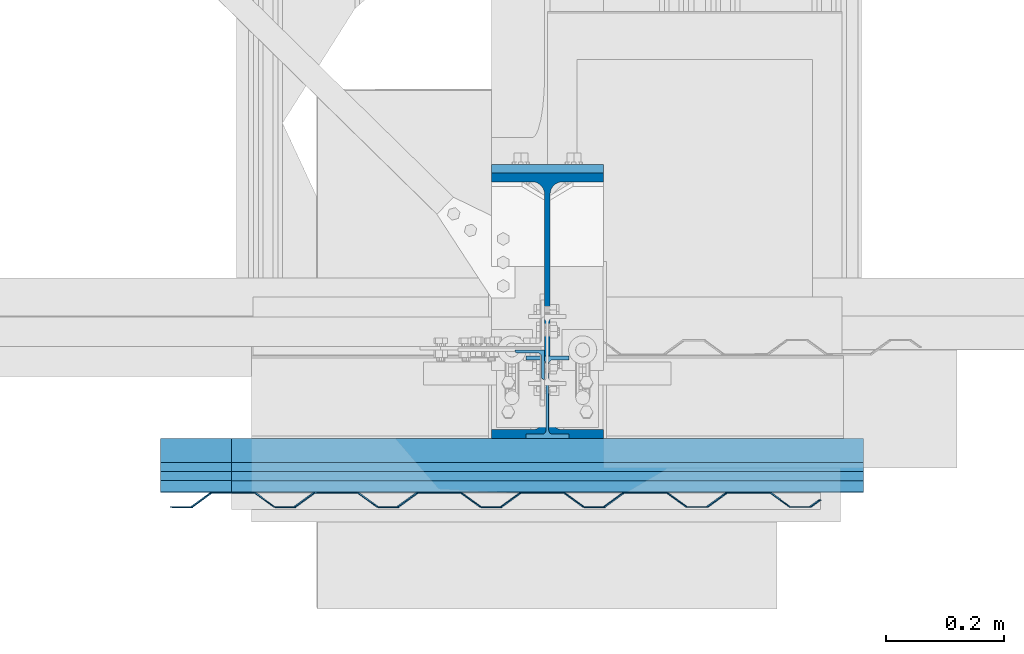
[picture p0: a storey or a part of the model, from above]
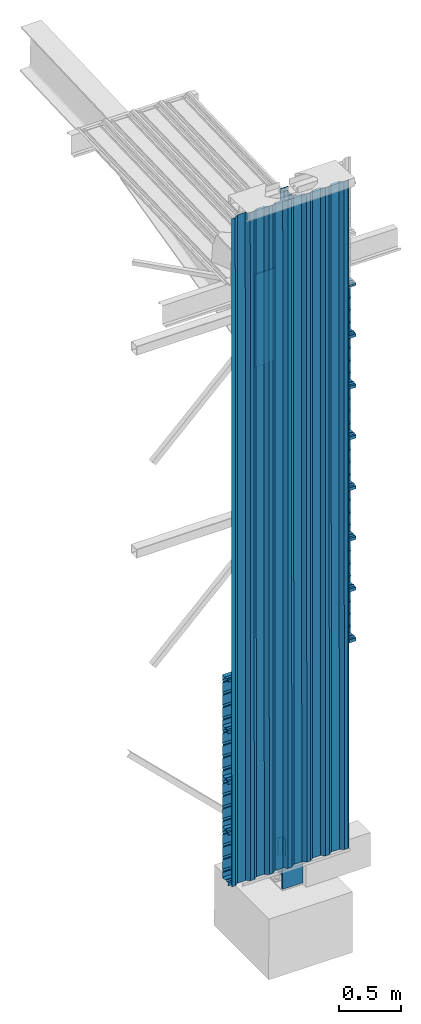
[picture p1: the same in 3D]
Properties of the parts of a building model (IFC2X3)

# File
Description: ViewDefinition [CoordinationView, QuantityTakeOffAddOnView]
File name: u52_2007v4.ifc
Time: 2011-07-12T17:19:12
Author: PORTCM01/professeur
Organization: Structural Designer
Written by: IFC Database Version:Work
Made in: Tekla Structures 18.1 Build:12518/10.9.2012, IFC Export Version: 309Mar 29 2012

# IfcSite, Undefined
RefElevation: 0 mm

# IfcBuildingStorey, Undefined
In: Undefined
Elevation: 0 mm

# IfcBeam: 100*8 (3)
In: Undefined
Description: 100*8; Material: STEEL/S235JR
Tekla Common - Phase: 1; Class: 2; Grade: S235JR; Profile: 100*8; sets with these values: 2
Tekla Quantity - Height: 100 mm; Width: 8 mm; sets with these values: 2
Name | Center of gravity Z (mm) | Center of gravity Y (mm) | Center of gravity X (mm) | Bottom elevation | Top elevation | Part mark | Assembly mark | Name | Net weight (kg) = Gross weight (kg) = Weight (kg) = NetWeight (kg) | Net volume (m3) = Gross volume (m3) = NetVolume (m3) | Gross footprint area (m2) | Area per tons (m2) | Net surface area (m2) = Gross area (m2) = OuterSurfaceArea (m2) | Tekla Quantity, Length (mm) = BaseQuantities, Length (mm)
plat | 5896.02 | -156.908 | 44.4493 | +5.892 | +5.900 | A13 | A13 | plat | 0.52752 | 0.0000672 | 0.0084 | 37.428 | 0.019744 | 84
ABOUT BAIONNETTE | 6526 | -155 | 9.55507e-08 | +6.522 | +6.530 | 25(?) | P3(?) | ABOUT BAIONNETTE | 1.08456 | 0.00013816 | 0.01727 | 35.8702 | 0.0389032 | 172.7
plat | 5896.02 | -156.908 | -44.4507 | +5.892 | +5.900 | 26 | P3(?) | plat | 0.52752 | 0.0000672 | 0.0084 | 37.428 | 0.019744 | 84

# IfcBeam: 1000*0.63 (2)
In: Undefined
Description: 1000*0.63; Material: STEEL/S235JR
Tekla Common - Phase: 1; Grade: S235JR; Profile: 1000*0.63; sets with these values: 2
Tekla Quantity - Height: 1000 mm; Width: 0.63 mm; sets with these values: 2
Name | Center of gravity Z (mm) | Center of gravity Y (mm) | Center of gravity X (mm) | Bottom elevation | Top elevation | Part mark = Assembly mark | Class | Name | Net weight (kg) = Weight (kg) = NetWeight (kg) | Gross weight (kg) | Net volume (m3) = NetVolume (m3) | Gross volume (m3) | Gross footprint area (m2) | Area per tons (m2) | Net surface area (m2) = OuterSurfaceArea (m2) | Gross area (m2) | Tekla Quantity, Length (mm) = BaseQuantities, Length (mm)
BAVETTE | -2.53135 | -331.446 | -36.5 | -0.027 | +0.031 | B0(?) | 6 | BAVETTE | 0.496489 | 0.496489 | 0.000063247 | 0.000063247 | 0.00063 | 407.201 | 0.20217 | 0.20217 | 98.3257
COIFFE ACROTERE | 6582.44 | -240.452 | -1.03851 | +6.511 | +6.611 | A16(?) | 7 | COIFFE ACROTERE | 1.88091 | 2.51264 | 0.000239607 | 0.000320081 | 0 | 405.745 | 0.763172 | 1.01803 | 505.386

# IfcBeam: 1000*1.5, COSTIERE
In: Undefined
Description: 1000*1.5; Material: STEEL/S235JR
Tekla Common - Center of gravity Z: 5809.49 mm; Center of gravity Y: -69.3239 mm; Center of gravity X: 0.00000972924 mm; Bottom elevation: +5.728; Top elevation: +5.960; Part mark: A12(?); Assembly mark: A12(?); Phase: 1; Class: 2; Grade: S235JR; Profile: 1000*1.5; Name: COSTIERE; sets with these values: 2
Tekla Quantity - Net weight: 3.88528 kg; Gross weight: 3.88528 kg; Weight: 3.88528 kg; Net volume: 0.00049494 m3; Gross volume: 0.00049494 m3; Gross footprint area: 0.0015 m2; Area per tons: 170.878 m2; Net surface area: 0.66391 m2; Gross area: 0.66391 m2; Height: 1000 mm; Width: 1.5 mm; Length: 328.46 mm; sets with these values: 2
BaseQuantities - Length: 328.46 mm; OuterSurfaceArea: 0.66391 m2; NetVolume: 0.00049494 m3; NetWeight: 3.88528 kg

# IfcBeam: 200*330, LONGRINE
In: Undefined
Description: 200*330; Material: CONCRETE/C30/37
Tekla Common - Center of gravity Z: -135.07 mm; Center of gravity Y: -174.995 mm; Center of gravity X: 395 mm; Bottom elevation: -0.300; Top elevation: +0.030; Part mark: Da0(?); Assembly mark: Da0(?); Phase: 1; Class: 11; Grade: C30/37; Profile: 200*330; Name: LONGRINE; sets with these values: 2
Tekla Quantity - Net weight: 95.04 kg; Gross weight: 95.04 kg; Weight: 95.04 kg; Net volume: 0.0396 m3; Gross volume: 0.0396 m3; Gross footprint area: 0.12 m2; Area per tons: 8.08081 m2; Net surface area: 0.768 m2; Gross area: 0.768 m2; Height: 200 mm; Width: 330 mm; Length: 600 mm; sets with these values: 2
BaseQuantities - Length: 600 mm; OuterSurfaceArea: 0.768 m2; NetVolume: 0.0396 m3; NetWeight: 95.04 kg

# IfcBeam: 400*1, ELASTOPHENE SOPREMA
In: Undefined
Description: 400*1; Material: MISCELLANEOUS/NEOPRENE
Tekla Common - Center of gravity Z: 5833.66 mm; Center of gravity Y: 112.649 mm; Center of gravity X: 250 mm; Bottom elevation: +5.810; Top elevation: +5.959; Part mark: B0(?); Assembly mark: B0(?); Phase: 1; Class: 8; Grade: NEOPRENE; Profile: 400*1; Name: ELASTOPHENE SOPREMA; sets with these values: 2
Tekla Quantity - Net weight: 0.461503 kg; Gross weight: 0.461503 kg; Weight: 0.461503 kg; Net volume: 0.000256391 m3; Gross volume: 0.000256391 m3; Gross footprint area: 0.0004 m2; Area per tons: 1115.62 m2; Net surface area: 0.514863 m2; Gross area: 0.514863 m2; Height: 400 mm; Width: 1 mm; Length: 640.174 mm; sets with these values: 2
BaseQuantities - Length: 640.174 mm; OuterSurfaceArea: 0.514863 m2; NetVolume: 0.000256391 m3; NetWeight: 0.461503 kg

# IfcBeam: 80*500, PANNEAUTOIT FIBAC 2
In: Undefined
Description: 80*500; Material: MISCELLANEOUS/ISOLANT
Tekla Common - Center of gravity Z: 5776.99 mm; Center of gravity Y: 226.647 mm; Center of gravity X: 229.049 mm; Bottom elevation: +5.730; Top elevation: +5.823; Part mark: B0(?); Assembly mark: B0(?); Phase: 1; Class: 13; Grade: ISOLANT; Profile: 80*500; Name: PANNEAUTOIT FIBAC 2; sets with these values: 2
Tekla Quantity - Net weight: 0 kg; Gross weight: 0 kg; Weight: 0 kg; Net volume: 0.0201058 m3; Gross volume: 0.023111 m3; Gross footprint area: 0 m2; Net surface area: 0.808896 m2; Gross area: 0.750218 m2; Height: 80 mm; Width: 500 mm; Length: 577.774 mm; sets with these values: 2
BaseQuantities - Length: 577.774 mm; OuterSurfaceArea: 0.808896 m2; NetVolume: 0.0201058 m3; NetWeight: 0 kg

# IfcBeam: ARCLAD_FPB_MURESCO_1.500.90_BS_75 (13)
In: Undefined
Description: ARCLAD_FPB_MURESCO_1.500.90_BS_75; Material: STEEL/S235JR
Tekla Common - Part mark: A17(?); Assembly mark: A17(?); Phase: 1; Class: 3; Grade: S235JR; Profile: ARCLAD_FPB_MURESCO_1.500.90_BS_75; Name: BAC; sets with these values: 2
Tekla Quantity - Net weight: 6.45229 kg; Gross weight: 4.55687 kg; Weight: 4.55687 kg; Net volume: 0.000821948 m3; Gross volume: 0.000580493 m3; Gross footprint area: 0.064498 m2; Area per tons: 361.588 m2; Net surface area: 1.64771 m2; Gross area: 0 m2; Height: 92 mm; Width: 529 mm; Length: 1073 mm; sets with these values: 2
BaseQuantities - Length: 1073 mm; OuterSurfaceArea: 1.64771 m2; NetVolume: 0.000821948 m3; NetWeight: 6.45229 kg
Name | Center of gravity Z (mm) | Center of gravity Y (mm) | Center of gravity X (mm) | Bottom elevation | Top elevation
BAC | 273.805 | -244.806 | -120 | +0.001 | +0.530
BAC | 773.805 | -244.806 | -120 | +0.501 | +1.030
BAC | 1273.81 | -244.806 | -120 | +1.001 | +1.530
BAC | 1773.81 | -244.806 | -120 | +1.501 | +2.030
BAC | 2273.95 | -244.81 | 1.8531e-11 | +2.001 | +2.530
BAC | 3273.95 | -244.81 | 3.52429e-12 | +3.001 | +3.530
BAC | 2773.95 | -244.81 | 7.95808e-13 | +2.501 | +3.030
BAC | 3773.95 | -244.81 | -1.19371e-11 | +3.501 | +4.030
BAC | 4273.95 | -244.825 | 3.94493e-11 | +4.001 | +4.530
BAC | 4773.95 | -244.841 | -9.20863e-12 | +4.501 | +5.030
BAC | 5273.95 | -244.857 | 2.34195e-11 | +5.001 | +5.530
BAC | 5773.95 | -244.873 | 2.44427e-11 | +5.501 | +6.030
BAC | 6273.95 | -244.889 | -6.13909e-12 | +6.001 | +6.530

# IfcBeam: ARCLAD_TSE_TOITESCO_4.1035.34_SRP_75, BAC SUPPORT
In: Undefined
Description: ARCLAD_TSE_TOITESCO_4.1035.34_SRP_75; Material: STEEL/S235JR
Tekla Common - Center of gravity Z: 5743.41 mm; Center of gravity Y: 1222.38 mm; Center of gravity X: 20.6648 mm; Bottom elevation: +5.693; Top elevation: +5.806; Part mark: A11(?); Assembly mark: A11(?); Phase: 1; Class: 5; Grade: S235JR; Profile: ARCLAD_TSE_TOITESCO_4.1035.34_SRP_75; Name: BAC SUPPORT; sets with these values: 2
Tekla Quantity - Net weight: 21.597 kg; Gross weight: 16.7955 kg; Weight: 16.7955 kg; Net volume: 0.00275121 m3; Gross volume: 0.00213955 m3; Gross footprint area: 0 m2; Area per tons: 328.013 m2; Net surface area: 5.50914 m2; Gross area: 0 m2; Height: 33 mm; Width: 1060.73 mm; Length: 2406.69 mm; sets with these values: 2
BaseQuantities - Length: 2406.69 mm; OuterSurfaceArea: 5.50914 m2; NetVolume: 0.00275121 m3; NetWeight: 21.597 kg

# IfcBeam: ARVAL_FBV_HACIERBA_6.175.25_B_63 (2)
In: Undefined
Description: ARVAL_FBV_HACIERBA_6.175.25_B_63; Material: STEEL/S235JR
Tekla Common - Phase: 1; Grade: S235JR; Profile: ARVAL_FBV_HACIERBA_6.175.25_B_63; sets with these values: 2
Tekla Quantity - Gross footprint area: 0 m2; Gross area: 0 m2; Height: 25 mm; sets with these values: 2
Name | Center of gravity Z (mm) | Center of gravity Y (mm) | Center of gravity X (mm) | Bottom elevation | Top elevation | Part mark = Assembly mark | Class | Name | Net weight (kg) = NetWeight (kg) | Gross weight (kg) = Weight (kg) | Net volume (m3) = NetVolume (m3) | Gross volume (m3) | Area per tons (m2) | Net surface area (m2) = OuterSurfaceArea (m2) | Width (mm) | Tekla Quantity, Length (mm) = BaseQuantities, Length (mm)
PEAU EXTERIEURE | 3295.08 | -327.825 | -86.1097 | -0.000 | +6.590 | A15(?) | 12 | PEAU EXTERIEURE | 64.4229 | 35.0222 | 0.00820673 | 0.00446143 | 451.669 | 15.8185 | 1101.65 | 6590
CONTREBARDAGE | 6239.31 | -72.7459 | 377.01 | +5.887 | +6.591 | A14(?) | 14 | CONTREBARDAGE | 3.20425 | 3.73031 | 0.000408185 | 0.000475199 | 211.574 | 0.789236 | 538.054 | 701.919

# IfcBeam: D24 (2)
In: Undefined
Description: D24; Material: STEEL/S235JR
Tekla Common - Center of gravity Z: -525.468 mm; Center of gravity Y: -90.0942 mm; Bottom elevation: -0.735; Top elevation: -0.235; Part mark: B0(?); Assembly mark: B0(?); Phase: 1; Class: 10; Grade: S235JR; Profile: D24; Name: CROSSE; sets with these values: 2
Tekla Quantity - Net weight: 2.12597 kg; Gross weight: 2.12597 kg; Weight: 2.12597 kg; Net volume: 0.000270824 m3; Gross volume: 0.000270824 m3; Gross footprint area: 0.000432 m2; Area per tons: 22.4285 m2; Net surface area: 0.0476824 m2; Gross area: 0.0476824 m2; Height: 24 mm; Width: 24 mm; Length: 592.507 mm; sets with these values: 2
BaseQuantities - Length: 592.507 mm; OuterSurfaceArea: 0.0476824 m2; NetVolume: 0.000270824 m3; NetWeight: 2.12597 kg
Name | Center of gravity X (mm)
CROSSE | -60
CROSSE | 60

# IfcBeam: D40, CLE
In: Undefined
Description: D40; Material: STEEL/S235JR
Tekla Common - Center of gravity Z: -691 mm; Center of gravity Y: -115.001 mm; Center of gravity X: -3.18869e-09 mm; Bottom elevation: -0.711; Top elevation: -0.671; Part mark: B0(?); Assembly mark: B0(?); Phase: 1; Class: 6; Grade: S235JR; Profile: D40; Name: CLE; sets with these values: 2
Tekla Quantity - Net weight: 3.9564 kg; Gross weight: 3.9564 kg; Weight: 3.9564 kg; Net volume: 0.000504 m3; Gross volume: 0.000504 m3; Gross footprint area: 0 m2; Area per tons: 13.7948 m2; Net surface area: 0.0545779 m2; Gross area: 0.0545779 m2; Height: 40 mm; Width: 40 mm; Length: 420 mm; sets with these values: 2
BaseQuantities - Length: 420 mm; OuterSurfaceArea: 0.0545779 m2; NetVolume: 0.000504 m3; NetWeight: 3.9564 kg

# IfcBeam: IPE120, BECHE
In: Undefined
Description: IPE120; Material: STEEL/S235JR
Tekla Common - Center of gravity Z: -350 mm; Center of gravity Y: -75.0003 mm; Center of gravity X: -3.07782e-08 mm; Bottom elevation: -0.400; Top elevation: -0.300; Part mark: E0; Assembly mark: E0(?); Phase: 1; Class: 2; Grade: S235JR; Profile: IPE120; Name: BECHE; sets with these values: 2
Tekla Quantity - Net weight: 1.00398 kg; Gross weight: 1.0362 kg; Weight: 1.0362 kg; Net volume: 0.000127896 m3; Gross volume: 0.000132 m3; Gross footprint area: 0.00127896 m2; Area per tons: 45.8406 m2; Net surface area: 0.0512779 m2; Gross area: 0.0475 m2; Height: 120 mm; Width: 64 mm; Length: 100 mm; sets with these values: 2
BaseQuantities - Length: 100 mm; OuterSurfaceArea: 0.0475 m2; NetVolume: 0.000127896 m3; NetWeight: 1.00398 kg

# IfcBeam: IPE450 (2)
In: Undefined
Description: IPE450; Material: STEEL/S235JR
Tekla Common - Assembly mark: A1(?); Phase: 1; Grade: S235JR; Profile: IPE450; sets with these values: 2
Tekla Quantity - Gross footprint area: 0 m2; Area per tons: 20.6942 m2; Width: 190 mm; sets with these values: 2
Name | Center of gravity Z (mm) | Center of gravity Y (mm) | Center of gravity X (mm) | Bottom elevation | Top elevation | Part mark | Class | Name | Net weight (kg) = NetWeight (kg) | Gross weight (kg) = Weight (kg) | Net volume (m3) = NetVolume (m3) | Gross volume (m3) | Net surface area (m2) | Gross area (m2) = OuterSurfaceArea (m2) | Height (mm) | Tekla Quantity, Length (mm) = BaseQuantities, Length (mm)
JARRET | 4902.21 | 1165.32 | 2.32655e-12 | +4.602 | +5.146 | 3(?) | 99 | JARRET | 165.891 | 180.998 | 0.0211326 | 0.0230571 | 3.66903 | 3.74561 | 444.517 | 2333.71
POUTRE | 5359.44 | 2124.5 | 1.81463e-12 | +5.059 | +5.660 | 2 | 1 | POUTRE | 281.402 | 293.247 | 0.0358473 | 0.0373563 | 6.20963 | 6.06852 | 450 | 3781.01

# IfcBeam: L40*4, DIAGONALE PAV
In: Undefined
Description: L40*4; Material: STEEL/S235JR
Tekla Common - Center of gravity Z: 5514.53 mm; Center of gravity Y: 477.806 mm; Center of gravity X: -499.603 mm; Bottom elevation: +5.472; Top elevation: +5.540; Part mark: A4(?); Assembly mark: A4(?); Phase: 1; Class: 9; Grade: S235JR; Profile: L40*4; Name: DIAGONALE PAV; sets with these values: 2
Tekla Quantity - Net weight: 2.52387 kg; Gross weight: 2.55887 kg; Weight: 2.55887 kg; Net volume: 0.000321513 m3; Gross volume: 0.00032597 m3; Gross footprint area: 0 m2; Area per tons: 64.1079 m2; Net surface area: 0.169827 m2; Gross area: 0.164043 m2; Height: 40 mm; Width: 40 mm; Length: 1058.34 mm; sets with these values: 2
BaseQuantities - Length: 1058.34 mm; OuterSurfaceArea: 0.164043 m2; NetVolume: 0.000321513 m3; NetWeight: 2.52387 kg

# IfcBeam: L50*5 (4)
In: Undefined
Description: L50*5; Material: STEEL/S235JR
Tekla Common - Phase: 1; Grade: S235JR; Profile: L50*5; sets with these values: 2
Tekla Quantity - Area per tons: 51.4862 m2; Height: 50 mm; Width: 50 mm; sets with these values: 2
Name | Center of gravity Z (mm) | Center of gravity Y (mm) | Center of gravity X (mm) | Bottom elevation | Top elevation | Part mark = Assembly mark | Class | Name | Net weight (kg) = NetWeight (kg) | Gross weight (kg) = Weight (kg) | Net volume (m3) = NetVolume (m3) | Gross volume (m3) | Gross footprint area (m2) | Net surface area (m2) | Gross area (m2) = OuterSurfaceArea (m2) | Tekla Quantity, Length (mm) = BaseQuantities, Length (mm)
DIAGONALE CV | 2780.98 | -54.6579 | -630.38 | +2.188 | +3.359 | A8(?) | 9 | DIAGONALE CV | 6.06359 | 6.12742 | 0.000772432 | 0.000780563 | 0 | 0.326185 | 0.315477 | 1626.17
DIAGONALE CV | 762.976 | -54.6579 | -750.51 | +0.073 | +1.437 | A5(?) | 9 | DIAGONALE CV | 7.09243 | 7.16709 | 0.000903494 | 0.000913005 | 0 | 0.381369 | 0.369006 | 1902.09
DIAGONALE CV | 4780.98 | -54.6579 | -630.38 | +4.188 | +5.359 | A8(?) | 9 | DIAGONALE CV | 6.06359 | 6.12742 | 0.000772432 | 0.000780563 | 0 | 0.326185 | 0.315477 | 1626.17
ATTACHE CV | 33.0846 | -54.6559 | -19.0421 | -0.054 | +0.121 | A6(?) | 2 | ATTACHE CV | 0.652531 | 0.6594 | 0.000083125 | 0.000084 | 0.000475 | 0.03595 | 0.03395 | 175

# IfcBeam: PD48*12 (4)
In: Undefined
Description: PD48*12; Material: STEEL/S235JR
Tekla Common - Center of gravity Y: -75 mm; Part mark: E0; Assembly mark: E0(?); Phase: 1; Class: 1; Grade: S235JR; Profile: PD48*12; sets with these values: 2
Tekla Quantity - Gross footprint area: 0.001296 m2; Height: 48 mm; Width: 48 mm; sets with these values: 2
Name | Center of gravity Z (mm) | Center of gravity X (mm) | Bottom elevation | Top elevation | Name | Net weight (kg) = Gross weight (kg) = Weight (kg) = NetWeight (kg) | Net volume (m3) = Gross volume (m3) = NetVolume (m3) | Area per tons (m2) | Net surface area (m2) = Gross area (m2) = OuterSurfaceArea (m2) | Tekla Quantity, Length (mm) = BaseQuantities, Length (mm)
RONDELLE | -269 | 60 | -0.275 | -0.263 | RONDELLE | 0.122083 | 0.000015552 | 28.8079 | 0.00351696 | 12
ECROU | -251 | -60 | -0.263 | -0.239 | ECROU | 0.244166 | 0.000031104 | 21.7307 | 0.00530591 | 24
RONDELLE | -269 | -60 | -0.275 | -0.263 | RONDELLE | 0.122083 | 0.000015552 | 28.8079 | 0.00351696 | 12
ECROU | -251 | 60 | -0.263 | -0.239 | ECROU | 0.244166 | 0.000031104 | 21.7307 | 0.00530591 | 24

# IfcBeam: PL10*190, CAP PLATE
In: Undefined
Description: PL10*190; Material: STEEL/S235JR
Tekla Common - Center of gravity Z: 5509 mm; Center of gravity Y: -5.88045e-11 mm; Center of gravity X: -1.07138e-09 mm; Bottom elevation: +5.504; Top elevation: +5.514; Part mark: F3; Assembly mark: P1(?); Phase: 1; Class: 99; Grade: S235JR; Profile: PL10*190; Name: CAP PLATE; sets with these values: 2
Tekla Quantity - Net weight: 6.53277 kg; Gross weight: 6.53277 kg; Weight: 6.53277 kg; Net volume: 0.0008322 m3; Gross volume: 0.0008322 m3; Gross footprint area: 0.08322 m2; Area per tons: 27.4003 m2; Net surface area: 0.179 m2; Gross area: 0.179 m2; Height: 190 mm; Width: 10 mm; Length: 438 mm; sets with these values: 2
BaseQuantities - Length: 438 mm; OuterSurfaceArea: 0.179 m2; NetVolume: 0.0008322 m3; NetWeight: 6.53277 kg

# IfcBeam: PL10*70 (2)
In: Undefined
Description: PL10*70; Material: STEEL/S235JR
Tekla Common - Center of gravity Z: -280 mm; Center of gravity Y: -75 mm; Bottom elevation: -0.285; Top elevation: -0.275; Part mark: P2(?); Assembly mark: P2(?); Phase: 1; Class: 2; Grade: S235JR; Profile: PL10*70; Name: CONTRE PLAQUE; sets with these values: 2
Tekla Quantity - Net weight: 0.38465 kg; Gross weight: 0.38465 kg; Weight: 0.38465 kg; Net volume: 0.000049 m3; Gross volume: 0.000049 m3; Gross footprint area: 0.0049 m2; Area per tons: 32.7571 m2; Net surface area: 0.0126 m2; Gross area: 0.0126 m2; Height: 70 mm; Width: 10 mm; Length: 70 mm; sets with these values: 2
BaseQuantities - Length: 70 mm; OuterSurfaceArea: 0.0126 m2; NetVolume: 0.000049 m3; NetWeight: 0.38465 kg
Name | Center of gravity X (mm)
CONTRE PLAQUE | 60
CONTRE PLAQUE | -60

# IfcBeam: PL15*200, PLATINE
In: Undefined
Description: PL15*200; Material: STEEL/S235JR
Tekla Common - Center of gravity Z: -292.5 mm; Center of gravity Y: -75 mm; Center of gravity X: -9.02299e-14 mm; Bottom elevation: -0.300; Top elevation: -0.285; Part mark: 4(?); Assembly mark: P1(?); Phase: 1; Class: 6; Grade: S235JR; Profile: PL15*200; Name: PLATINE; sets with these values: 2
Tekla Quantity - Net weight: 7.065 kg; Gross weight: 7.065 kg; Weight: 7.065 kg; Net volume: 0.0009 m3; Gross volume: 0.0009 m3; Gross footprint area: 0.06 m2; Area per tons: 19.1083 m2; Net surface area: 0.135 m2; Gross area: 0.135 m2; Height: 200 mm; Width: 15 mm; Length: 300 mm; sets with these values: 2
BaseQuantities - Length: 300 mm; OuterSurfaceArea: 0.135 m2; NetVolume: 0.0009 m3; NetWeight: 7.065 kg

# IfcBeam: PL8*90 (2)
In: Undefined
Description: PL8*90; Material: STEEL/S235JR
Tekla Common - Center of gravity Z: 4604.44 mm; Center of gravity Y: 2.84217e-14 mm; Bottom elevation: +4.600; Top elevation: +4.608; Part mark: F2; Assembly mark: P1(?); Phase: 1; Class: 99; Grade: S235JR; Profile: PL8*90; Name: TOLE; sets with these values: 2
Tekla Quantity - Net weight: 2.33459 kg; Gross weight: 2.37384 kg; Weight: 2.33459 kg; Net volume: 0.0002974 m3; Gross volume: 0.0003024 m3; Gross footprint area: 0.037175 m2; Area per tons: 35.242 m2; Net surface area: 0.0822757 m2; Gross area: 0.08376 m2; Height: 90 mm; Width: 8 mm; Length: 420 mm; sets with these values: 2
BaseQuantities - Length: 420 mm; OuterSurfaceArea: 0.0822757 m2; NetVolume: 0.0002974 m3; NetWeight: 2.33459 kg
Name | Center of gravity X (mm)
TOLE | -50.3165
TOLE | 50.3165

# IfcBeam: TUBE-C-90*90*3 (2)
In: Undefined
Description: TUBE-C-90*90*3; Material: STEEL/S235JR
Tekla Common - Phase: 1; Class: 9; Grade: S235JR; Profile: TUBE-C-90*90*3; sets with these values: 2
Tekla Quantity - Gross weight: 11.095 kg; Weight: 11.095 kg; Gross volume: 0.00141337 m3; Area per tons: 43.5442 m2; Gross area: 0.483121 m2; Height: 90 mm; Width: 90 mm; Length: 1384.3 mm; sets with these values: 2
BaseQuantities - Length: 1384.3 mm; OuterSurfaceArea: 0.483121 m2
Name | Center of gravity Z (mm) | Center of gravity Y (mm) | Center of gravity X (mm) | Bottom elevation | Top elevation | Part mark = Assembly mark | Name | Net weight (kg) = NetWeight (kg) | Net volume (m3) = NetVolume (m3) | Gross footprint area (m2) | Net surface area (m2)
TRAVERSE CV | 3414 | -74.9963 | -705.227 | +3.369 | +3.459 | A9(?) | TRAVERSE CV | 11.3027 | 0.00143983 | 0.12369 | 0.498269
BUTON | 5413.99 | -74.9956 | -705.599 | +5.369 | +5.459 | A10(?) | BUTON | 11.2953 | 0.00143889 | 0.123475 | 0.498067

# IfcBeam: UPF-140*60*4 (4)
In: Undefined
Description: UPF-140*60*4; Material: STEEL/S235JR
Tekla Common - Phase: 1; Class: 6; Grade: S235JR; Profile: UPF-140*60*4; sets with these values: 2
Tekla Quantity - Net weight: 3.60705 kg; Gross weight: 3.53333 kg; Weight: 3.53333 kg; Net volume: 0.000459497 m3; Gross volume: 0.000450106 m3; Gross footprint area: 0.0036468 m2; Area per tons: 66.6258 m2; Net surface area: 0.235411 m2; Gross area: 0 m2; Height: 140 mm; Width: 60 mm; Length: 455.85 mm; sets with these values: 2
BaseQuantities - Length: 455.85 mm; OuterSurfaceArea: 0.235411 m2; NetVolume: 0.000459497 m3; NetWeight: 3.60705 kg
Name | Center of gravity Z (mm) | Center of gravity Y (mm) | Center of gravity X (mm) | Bottom elevation | Top elevation | Part mark = Assembly mark | Name
LISSE BASSE | 5914.88 | -154.978 | 274.424 | +5.900 | +5.960 | A20(?) | LISSE BASSE
LISSE HAUTE | 6545.33 | -155 | -274.425 | +6.530 | +6.590 | A19(?) | LISSE HAUTE
LISSE BASSE | 5914.88 | -154.978 | -274.425 | +5.900 | +5.960 | A18(?) | LISSE BASSE
LISSE HAUTE | 6545.33 | -155 | 274.425 | +6.530 | +6.590 | A19(?) | LISSE HAUTE

# IfcBeam: Z.180.150.65 (2)
In: Undefined
Description: Z.180.150.65; Material: STEEL/S235JR
Tekla Common - Phase: 1; Class: 5; Grade: S235JR; Profile: Z.180.150.65; sets with these values: 2
Tekla Quantity - Gross area: 0 m2; Height: 180 mm; Width: 123 mm; sets with these values: 2
Name | Center of gravity Z (mm) | Center of gravity Y (mm) | Center of gravity X (mm) | Bottom elevation | Top elevation | Part mark = Assembly mark | Name | Net weight (kg) = NetWeight (kg) | Gross weight (kg) = Weight (kg) | Net volume (m3) = NetVolume (m3) | Gross volume (m3) | Gross footprint area (m2) | Area per tons (m2) | Net surface area (m2) = OuterSurfaceArea (m2) | Tekla Quantity, Length (mm) = BaseQuantities, Length (mm)
PANNE SABLIERE | 5605.43 | -15.428 | 4.09273e-12 | +5.514 | +5.694 | A3(?) | PANNE SABLIERE | 8.85792 | 8.50979 | 0.0011284 | 0.00108405 | 0.14235 | 177.693 | 1.51213 | 2190
PANNE | 5684.57 | 2329.91 | 1.93268e-12 | +5.593 | +5.773 | A2(?) | PANNE | 4.81321 | 4.62404 | 0.000613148 | 0.00058905 | 0.07735 | 177.795 | 0.82213 | 1190

# IfcColumn: IPE140, BAIONNETTE
In: Undefined
Description: IPE140; Material: STEEL/S235JR
Tekla Common - Center of gravity Z: 6018 mm; Center of gravity Y: -155 mm; Center of gravity X: 3.18745e-12 mm; Bottom elevation: +5.514; Top elevation: +6.522; Part mark: 8(?); Assembly mark: P3(?); Phase: 1; Class: 7; Grade: S235JR; Profile: IPE140; Name: BAIONNETTE; sets with these values: 2
Tekla Quantity - Net weight: 12.6648 kg; Gross weight: 12.977 kg; Weight: 12.977 kg; Net volume: 0.00161335 m3; Gross volume: 0.00165312 m3; Gross footprint area: 0.00160054 m2; Area per tons: 42.7994 m2; Net surface area: 0.570302 m2; Gross area: 0.555408 m2; Height: 140 mm; Width: 73 mm; Length: 1008 mm; sets with these values: 2
BaseQuantities - Length: 1008 mm; OuterSurfaceArea: 0.555408 m2; NetVolume: 0.00161335 m3; NetWeight: 12.6648 kg

# IfcColumn: IPE450, POTEAU
In: Undefined
Description: IPE450; Material: STEEL/S235JR
Tekla Common - Center of gravity Z: 2609.5 mm; Center of gravity Y: -1.9305e-13 mm; Center of gravity X: 1.62511e-15 mm; Bottom elevation: -0.285; Top elevation: +5.504; Part mark: 1; Assembly mark: P1(?); Phase: 1; Class: 1; Grade: S235JR; Profile: IPE450; Name: POTEAU; sets with these values: 2
Tekla Quantity - Net weight: 431.875 kg; Gross weight: 448.983 kg; Weight: 448.983 kg; Net volume: 0.0550159 m3; Gross volume: 0.0571953 m3; Gross footprint area: 0.00950352 m2; Area per tons: 20.6942 m2; Net surface area: 9.51991 m2; Gross area: 9.29134 m2; Height: 450 mm; Width: 190 mm; Length: 5789 mm; sets with these values: 2
BaseQuantities - Length: 5789 mm; OuterSurfaceArea: 9.29134 m2; NetVolume: 0.0550159 m3; NetWeight: 431.875 kg

# IfcColumn: L50*5, ATTACHE CV
In: Undefined
Description: L50*5; Material: STEEL/S235JR
Tekla Common - Center of gravity Z: 33.0835 mm; Center of gravity Y: -89.3401 mm; Center of gravity X: -19.0421 mm; Bottom elevation: -0.054; Top elevation: +0.121; Part mark: A7(?); Assembly mark: A7(?); Phase: 1; Class: 2; Grade: S235JR; Profile: L50*5; Name: ATTACHE CV; sets with these values: 2
Tekla Quantity - Net weight: 0.652531 kg; Gross weight: 0.6594 kg; Weight: 0.6594 kg; Net volume: 0.000083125 m3; Gross volume: 0.000084 m3; Gross footprint area: 0.000475 m2; Area per tons: 51.4862 m2; Net surface area: 0.03595 m2; Gross area: 0.03395 m2; Height: 50 mm; Width: 50 mm; Length: 175 mm; sets with these values: 2
BaseQuantities - Length: 175 mm; OuterSurfaceArea: 0.03395 m2; NetVolume: 0.000083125 m3; NetWeight: 0.652531 kg

# IfcColumn: PL15*190, PLATINE
In: Undefined
Description: PL15*190; Material: STEEL/S235JR
Tekla Common - Center of gravity Z: 5046.5 mm; Center of gravity Y: 232.5 mm; Center of gravity X: 2.31065e-12 mm; Bottom elevation: +4.589; Top elevation: +5.504; Part mark: F1(?); Assembly mark: A1(?); Phase: 1; Class: 99; Grade: S235JR; Profile: PL15*190; Name: PLATINE; sets with these values: 2
Tekla Quantity - Net weight: 20.4708 kg; Gross weight: 20.4708 kg; Weight: 20.4708 kg; Net volume: 0.00260775 m3; Gross volume: 0.00260775 m3; Gross footprint area: 0.00285 m2; Area per tons: 18.6045 m2; Net surface area: 0.38085 m2; Gross area: 0.38085 m2; Height: 190 mm; Width: 15 mm; Length: 915 mm; sets with these values: 2
BaseQuantities - Length: 915 mm; OuterSurfaceArea: 0.38085 m2; NetVolume: 0.00260775 m3; NetWeight: 20.4708 kg

# IfcElementAssembly (57)
In: Undefined
Tekla Assembly - sets with these values: 2
Name | Assembly/Cast unit weight (kg) | Assembly/Cast unit bottom elevation | Assembly/Cast unit top elevation | Assembly/Cast unit name | Assembly/Cast unit Mark
plat | 0.52752 | +5.892 | +5.900 | plat | A13
lisseBasse | 0 | +5.900 | +5.960 | lisseBasse | A20(?)
etancheite | 0.461503 | +5.810 | +5.959 | etancheite | B0(?)
isolant | 0 | +5.730 | +5.823 | isolant | B0(?)
clé | 0 | -0.711 | -0.671 | clé | B0(?)
massif | 725.495 | -0.902 | -0.296 | massif | Da0(?) | PredefinedType: REINFORCEMENT_UNIT; Tekla Assembly - Cast unit rebar weight: 0 kg
BECHE | 0 | -0.400 | -0.300 | BECHE | E0(?)
bavette | 0.496489 | -0.027 | +0.031 | bavette | B0(?)
bac | 0 | +0.001 | +0.530 | bac | A17(?)
bac | 0 | +0.501 | +1.030 | bac | A17(?)
bac | 0 | +1.001 | +1.530 | bac | A17(?)
bac | 0 | +1.501 | +2.030 | bac | A17(?)
bac | 0 | +2.001 | +2.530 | bac | A17(?)
bac | 0 | +2.501 | +3.030 | bac | A17(?)
2 x plaque | 0.38465 | -0.285 | -0.275 | plaque | P2(?)
Assembly | 0 | -0.735 | -0.235 | Assembly | B0(?)
BARRE | 0 | -0.735 | -0.235 | BARRE | B0(?)
Assembly | 0 | -0.275 | -0.263 | Assembly | E0(?)
bac | 0 | +3.001 | +3.530 | bac | A17(?)
RONDELLE | 0 | -0.275 | -0.263 | RONDELLE | E0(?)
ECROU | 0 | -0.263 | -0.239 | ECROU | E0(?)
Assembly | 0 | -0.263 | -0.239 | Assembly | E0(?)
massif | 95.04 | -0.300 | +0.030 | massif | Da0(?) | PredefinedType: REINFORCEMENT_UNIT; Tekla Assembly - Cast unit rebar weight: 0 kg
coiffe | 1.88091 | +6.511 | +6.611 | coiffe | A16(?)
contrebardage | 0 | -0.000 | +6.590 | contrebardage | A15(?)
contrebardage | 0 | +5.887 | +6.591 | contrebardage | A14(?)
2 x lisseBasse | 0 | +6.530 | +6.590 | lisseBasse | A19(?)
bac | 0 | +3.501 | +4.030 | bac | A17(?)
bac | 0 | +4.001 | +4.530 | bac | A17(?)
bac | 0 | +4.501 | +5.030 | bac | A17(?)
bac | 0 | +5.001 | +5.530 | bac | A17(?)
bac | 0 | +5.501 | +6.030 | bac | A17(?)
lisseBasse | 0 | +5.900 | +5.960 | lisseBasse | A18(?)
costière | 3.88528 | +5.728 | +5.960 | costière | A12(?)
bac | 0 | +6.001 | +6.530 | bac | A17(?)
bac | 0 | +5.693 | +5.806 | bac | A11(?)
GOUSSET | 1.61457 | +3.334 | +3.469 | GOUSSET | G0(?)
GOUSSET | 1.26866 | +3.232 | +3.469 | GOUSSET | G0(?)
buton | 0 | +3.369 | +3.459 | buton | A9(?)
CV | 0 | +2.188 | +3.359 | CV | A8(?)
GOUSSET | 1.89425 | +5.232 | +5.469 | GOUSSET | G0(?)
GOUSSET | 1.53854 | +5.232 | +5.469 | GOUSSET | G0(?)
CV | 0 | +0.073 | +1.437 | CV | A5(?)
buton | 0 | +5.369 | +5.459 | buton | A10(?)
POUTRE | 20.4708 | +4.589 | +5.660 | POUTRE | A1(?)
POTEAU | 21.3493 | -0.300 | +5.514 | POTEAU | P1(?)
Baïonnette | 1.61208 | +5.514 | +6.530 | Baïonnette | P3(?)
POUTRE | 0 | +5.514 | +5.694 | POUTRE | A3(?)
POUTRE | 0 | +5.593 | +5.773 | POUTRE | A2(?)
diag | 0 | +5.472 | +5.540 | diag | A4(?)
GOUSSET | 0.613631 | +5.514 | +5.520 | GOUSSET | G0(?)
CV | 0 | +4.188 | +5.359 | CV | A8(?)
CV | 0 | -0.054 | +0.121 | CV | A6(?)
CV | 0 | -0.054 | +0.121 | CV | A7(?)
GOUSSET | 1.38869 | -0.054 | +0.228 | GOUSSET | G0(?)

# IfcMechanicalFastener: Bolt assembly (20)
In: Undefined
Tekla Fastener - Slotted hole y: 0 mm; Slotted hole x: 0 mm; Location: Montage; sets with these values: 2
Name | NominalDiameter (mm) = Washer diameter (mm) = Bolt size (mm) | NominalLength (mm) = Bolt length (mm) | Washer count | Washer type | Washer name | Nut count = Bolt count | Nut type | Nut name | Bolt hole diameter (mm) | Bolt standard | Bolt Name
5 x Bolt assembly | 12 | 30 | 0 | PLA-8.8 | RONDELLE-M12-PLA-8.8 | 2 | E-8.8 | ECROU-M12-E-8.8 | 14 | 8.8 | M12*30
Bolt assembly | 16 | 40 | 0 | PLA-8.8 | RONDELLE-M16-PLA-8.8 | 4 | E-8.8 | ECROU-M16-E-8.8 | 18 | 8.8 | M16*40
2 x Bolt assembly | 12 | 30 | 0 | PLA-8.8 | RONDELLE-M12-PLA-8.8 | 3 | E-8.8 | ECROU-M12-E-8.8 | 14 | 8.8 | M12*30
Bolt assembly | 12 | 30 | 0 | PLA-8.8 | RONDELLE-M12-PLA-8.8 | 4 | E-8.8 | ECROU-M12-E-8.8 | 14 | 8.8 | M12*30
2 x Bolt assembly | 16 | 60 | 16 | PLA-HR8.8 | RONDELLE-M16-PLA-HR8.8 | 8 | E-HR8.8 | ECROU-M16-E-HR8.8 | 18 | HR8.8 | M16*60
2 x Bolt assembly | 12 | 30 | 0 | PLA-HR8.8 | RONDELLE-M12-PLA-HR8.8 | 1 | E-HR8.8 | ECROU-M12-E-HR8.8 | 14 | HR8.8 | M12*30
3 x Bolt assembly | 12 | 40 | 0 | PLA-HR8.8 | RONDELLE-M12-PLA-HR8.8 | 1 | E-HR8.8 | ECROU-M12-E-HR8.8 | 14 | HR8.8 | M12*40
3 x Bolt assembly | 14 | 35 | 0 | PLA-8.8 | RONDELLE-M14-PLA-8.8 | 3 | E-8.8 | ECROU-M14-E-8.8 | 16 | 8.8 | M14*35
Bolt assembly | 14 | 30 | 0 | PLA-8.8 | RONDELLE-M14-PLA-8.8 | 3 | E-8.8 | ECROU-M14-E-8.8 | 16 | 8.8 | M14*30

# IfcPlate: PL10*90 (2)
In: Undefined
Description: PL10*90; Material: STEEL/S235JR
Tekla Common - Center of gravity Z: -194.768 mm; Center of gravity Y: 136.424 mm; Bottom elevation: -0.285; Top elevation: -0.098; Part mark: 6; Assembly mark: P1(?); Phase: 1; Grade: S235JR; Profile: PL10*90; Name: RAIDISSEUR; sets with these values: 2
Tekla Quantity - Net weight: 1.54117 kg; Gross weight: 1.59965 kg; Weight: 1.54117 kg; Net volume: 0.000196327 m3; Gross volume: 0.000196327 m3; Gross footprint area: 0 m2; Area per tons: 29.4313 m2; Net surface area: 0.0453587 m2; Gross area: 0.0203777 m2; Height: 90.3 mm; Width: 10 mm; Length: 225.667 mm; sets with these values: 2
Name | Center of gravity X (mm) | Class
RAIDISSEUR | 51.075 | 99
RAIDISSEUR | -51.075 | 2

# IfcPlate: PL6*133, GOUSSET PAV
In: Undefined
Description: PL6*133; Material: STEEL/S235JR
Tekla Common - Center of gravity Z: 5517 mm; Center of gravity Y: 101.701 mm; Center of gravity X: -107.964 mm; Bottom elevation: +5.514; Top elevation: +5.520; Part mark: G0(?); Assembly mark: G0(?); Phase: 1; Class: 2; Grade: S235JR; Profile: PL6*133; Name: GOUSSET PAV; sets with these values: 2
Tekla Quantity - Net weight: 0.613631 kg; Gross weight: 1.06663 kg; Weight: 0.613631 kg; Net volume: 0.0000781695 m3; Gross volume: 0.0000781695 m3; Gross footprint area: 0.0130283 m2; Area per tons: 47.2141 m2; Net surface area: 0.0289721 m2; Gross area: 0.022646 m2; Height: 132.654 mm; Width: 6 mm; Length: 170.716 mm; sets with these values: 2

# IfcPlate: PL6*139, GOUSSET
In: Undefined
Description: PL6*139; Material: STEEL/S235JR
Tekla Common - Center of gravity Z: 3369.68 mm; Center of gravity Y: -74.9993 mm; Center of gravity X: -87.5003 mm; Bottom elevation: +3.232; Top elevation: +3.469; Part mark: G0; Assembly mark: G0(?); Phase: 1; Class: 6; Grade: S235JR; Profile: PL6*139; Name: GOUSSET; sets with these values: 2
Tekla Quantity - Net weight: 1.26866 kg; Gross weight: 1.54561 kg; Weight: 1.26866 kg; Net volume: 0.000161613 m3; Gross volume: 0.000171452 m3; Gross footprint area: 0.000832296 m2; Area per tons: 45.6306 m2; Net surface area: 0.0578898 m2; Gross area: 0.0328155 m2; Height: 138.716 mm; Width: 6 mm; Length: 236.566 mm; sets with these values: 2

# IfcPlate: PL6*141, GOUSSET
In: Undefined
Description: PL6*141; Material: STEEL/S235JR
Tekla Common - Center of gravity Z: 5352.75 mm; Center of gravity Y: -74.9996 mm; Center of gravity X: -79.9359 mm; Bottom elevation: +5.232; Top elevation: +5.469; Part mark: G0; Assembly mark: G0(?); Phase: 1; Class: 6; Grade: S235JR; Profile: PL6*141; Name: GOUSSET; sets with these values: 2
Tekla Quantity - Net weight: 1.53854 kg; Gross weight: 1.56799 kg; Weight: 1.53854 kg; Net volume: 0.000195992 m3; Gross volume: 0.000211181 m3; Gross footprint area: 0.000844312 m2; Area per tons: 45.3248 m2; Net surface area: 0.0697341 m2; Gross area: 0.0332906 m2; Height: 140.719 mm; Width: 6 mm; Length: 236.575 mm; sets with these values: 2

# IfcPlate: PL6*170, PLATINE ABOUT
In: Undefined
Description: PL6*170; Material: STEEL/S235JR
Tekla Common - Center of gravity Z: 5350.71 mm; Center of gravity Y: -74.9996 mm; Center of gravity X: -7.70001 mm; Bottom elevation: +5.232; Top elevation: +5.469; Part mark: G0(?); Assembly mark: G0(?); Phase: 1; Class: 2; Grade: S235JR; Profile: PL6*170; Name: PLATINE ABOUT; sets with these values: 2
Tekla Quantity - Net weight: 1.89425 kg; Gross weight: 1.89425 kg; Weight: 1.89425 kg; Net volume: 0.000241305 m3; Gross volume: 0.000241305 m3; Gross footprint area: 0.00102 m2; Area per tons: 45.0385 m2; Net surface area: 0.085314 m2; Gross area: 0.0402177 m2; Height: 170 mm; Width: 6 mm; Length: 236.575 mm; sets with these values: 2

# IfcPlate: PL6*211, GOUSSET
In: Undefined
Description: PL6*211; Material: STEEL/S235JR
Tekla Common - Center of gravity Z: 90.143 mm; Center of gravity Y: -71.9998 mm; Center of gravity X: -89.2125 mm; Bottom elevation: -0.054; Top elevation: +0.228; Part mark: G0; Assembly mark: G0(?); Phase: 1; Class: 6; Grade: S235JR; Profile: PL6*211; Name: GOUSSET; sets with these values: 2
Tekla Quantity - Net weight: 1.38869 kg; Gross weight: 2.80009 kg; Weight: 1.38869 kg; Net volume: 0.000176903 m3; Gross volume: 0.000176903 m3; Gross footprint area: 0 m2; Area per tons: 45.8096 m2; Net surface area: 0.0636154 m2; Gross area: 0.0594498 m2; Height: 210.606 mm; Width: 6 mm; Length: 282.28 mm; sets with these values: 2

# IfcPlate: PL8*135, GOUSSET
In: Undefined
Description: PL8*135; Material: STEEL/S235JR
Tekla Common - Center of gravity Z: 3401.34 mm; Center of gravity Y: -75 mm; Center of gravity X: -8.70001 mm; Bottom elevation: +3.334; Top elevation: +3.469; Part mark: G0; Assembly mark: G0(?); Phase: 1; Class: 2; Grade: S235JR; Profile: PL8*135; Name: GOUSSET; sets with these values: 2
Tekla Quantity - Net weight: 1.61457 kg; Gross weight: 1.61457 kg; Weight: 1.61457 kg; Net volume: 0.000205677 m3; Gross volume: 0.000205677 m3; Gross footprint area: 0.00152 m2; Area per tons: 35.0709 m2; Net surface area: 0.0566243 m2; Gross area: 0.0257097 m2; Height: 135.314 mm; Width: 8 mm; Length: 190 mm; sets with these values: 2

# IfcSlab: 600*780, MASSIF
In: Undefined
Description: 600*780; PredefinedType: FLOOR; Material: CONCRETE/C30/37 600 mm
Tekla Common - Center of gravity Z: -608.15 mm; Center of gravity Y: -135.646 mm; Center of gravity X: 12.81 mm; Bottom elevation: -0.902; Top elevation: -0.296; Part mark: Da0(?); Assembly mark: Da0(?); Phase: 1; Class: 11; Grade: C30/37; Profile: 600*780; Name: MASSIF; sets with these values: 2
Tekla Quantity - Net weight: 725.495 kg; Gross weight: 988.361 kg; Weight: 725.495 kg; Net volume: 0.30229 m3; Gross volume: 0.411812 m3; Gross footprint area: 0 m2; Area per tons: 6.10615 m2; Net surface area: 4.42998 m2; Gross area: 0.686362 m2; Height: 779.992 mm; Width: 600 mm; Length: 879.96 mm; sets with these values: 2
BaseQuantities - Width: 600 mm; NetVolume: 0.30229 m3; NetArea: 0 m2; NetWeight: 725.495 kg
